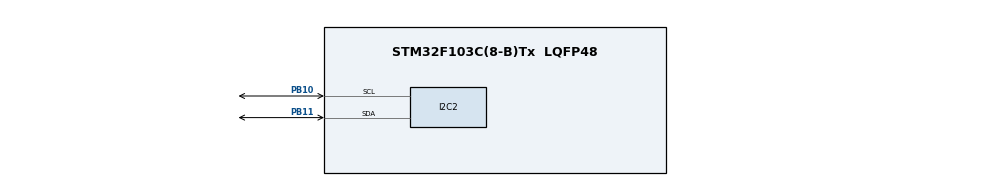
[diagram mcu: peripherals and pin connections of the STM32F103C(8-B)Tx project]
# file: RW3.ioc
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Mcu.Family=STM32F1
Mcu.Name=STM32F103C(8-B)Tx
Mcu.Package=LQFP48
NVIC.PriorityGroup=NVIC_PRIORITYGROUP_4
PA13.Mode=Serial_Wire
PA13.Signal=SYS_JTMS-SWDIO
PA14.Mode=Serial_Wire
PA14.Signal=SYS_JTCK-SWCLK
PB10.Mode=I2C
PB10.Signal=I2C2_SCL
PB11.Mode=I2C
PB11.Signal=I2C2_SDA
PD0-OSC_IN.Mode=HSE-External-Oscillator
PD0-OSC_IN.Signal=RCC_OSC_IN
PD1-OSC_OUT.Mode=HSE-External-Oscillator
PD1-OSC_OUT.Signal=RCC_OSC_OUT
ProjectManager.HeapSize=0x200
ProjectManager.StackSize=0x400
ProjectManager.TargetToolchain=MDK-ARM V5.32
RCC.AHBFreq_Value=72000000
RCC.APB1CLKDivider=RCC_HCLK_DIV2
RCC.APB1Freq_Value=36000000
RCC.APB1TimFreq_Value=72000000
RCC.APB2Freq_Value=72000000
RCC.APB2TimFreq_Value=72000000
RCC.HCLKFreq_Value=72000000
RCC.PLLMUL=RCC_PLL_MUL9
RCC.PLLSourceVirtual=RCC_PLLSOURCE_HSE
RCC.SYSCLKFreq_VALUE=72000000
RCC.SYSCLKSource=RCC_SYSCLKSOURCE_PLLCLK
RCC.USBFreq_Value=72000000
VP_TIM1_VS_ClockSourceINT.Mode=Internal
board=custom

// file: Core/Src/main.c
/* USER CODE BEGIN Header */
#include "main.h"
#include "i2c.h"
#include "tim.h"
#include "gpio.h"

/* USER CODE BEGIN Includes */
#include "u8g2.h"
/* USER CODE END Includes */

void SystemClock_Config(void);

/* USER CODE BEGIN 0 */
u8g2_t u8g2;
int x_offset = 0;

void Tims_delay_us(uint16_t us) {
    __HAL_TIM_SET_COUNTER(&htim1, 0);
    while (__HAL_TIM_GET_COUNTER(&htim1) < us);
}

uint8_t u8x8_byte_hw_i2c(u8x8_t *u8x8, uint8_t msg, uint8_t arg_int, void *arg_ptr) {
    static uint8_t buffer[128];
    static uint8_t buf_idx;
    uint8_t *data;

    switch (msg) {
    case U8X8_MSG_BYTE_INIT:
        break;
    case U8X8_MSG_BYTE_START_TRANSFER:
        buf_idx = 0;
        break;
    case U8X8_MSG_BYTE_SEND:
        data = (uint8_t *)arg_ptr;
        while (arg_int > 0) {
            buffer[buf_idx++] = *data;
            data++;
            arg_int--;
        }
        break;
    case U8X8_MSG_BYTE_END_TRANSFER:
        if (HAL_I2C_Master_Transmit(&hi2c2, 0x78, buffer, buf_idx, 1000) != HAL_OK)
            return 0;
        break;
    default:
        return 0;
    }
    return 1;
}

uint8_t u8x8_gpio_and_delay(u8x8_t *u8x8, uint8_t msg, uint8_t arg_int, void *arg_ptr) {
    switch (msg) {
    case U8X8_MSG_DELAY_100NANO:
        __NOP();
        break;
    case U8X8_MSG_DELAY_10MICRO:
        for (uint16_t n = 0; n < 320; n++) { __NOP(); }
        break;
    case U8X8_MSG_DELAY_MILLI:
        HAL_Delay(arg_int);
        break;
    case U8X8_MSG_DELAY_I2C:
        Tims_delay_us(5);
        break;
    default:
        u8x8_SetGPIOResult(u8x8, 1);
        break;
    }
    return 1;
}
/* USER CODE END 0 */

int main(void)
{
  HAL_Init();
  SystemClock_Config();
  MX_GPIO_Init();
  MX_I2C2_Init();
  MX_TIM1_Init();

  /* USER CODE BEGIN 2 */
  HAL_TIM_Base_Start(&htim1);

  u8g2_Setup_ssd1306_i2c_128x64_noname_f(&u8g2, U8G2_R0, u8x8_byte_hw_i2c, u8x8_gpio_and_delay);
  u8g2_InitDisplay(&u8g2);
  u8g2_SetPowerSave(&u8g2, 0);
  /* USER CODE END 2 */

  while (1)
  {
    /* USER CODE BEGIN 3 */
    u8g2_ClearBuffer(&u8g2);

    u8g2_DrawBox(&u8g2, 10, 10, 30, 30);
    u8g2_DrawCircle(&u8g2, 80, 30, 15, U8G2_DRAW_ALL);
    u8g2_DrawLine(&u8g2, 0, 0, 128, 64);
    u8g2_DrawLine(&u8g2, 0, 64, 128, 0);

    u8g2_DrawFrame(&u8g2, x_offset, 40, 16, 16);
    x_offset += 4;
    if (x_offset > 128) x_offset = 0;

    u8g2_SendBuffer(&u8g2);

    HAL_Delay(50);
    /* USER CODE END 3 */
  }
}

/* USER CODE BEGIN 4 */
void SystemClock_Config(void)
{
  RCC_OscInitTypeDef RCC_OscInitStruct = {0};
  RCC_ClkInitTypeDef RCC_ClkInitStruct = {0};

  RCC_OscInitStruct.OscillatorType = RCC_OSCILLATORTYPE_HSI;
  RCC_OscInitStruct.HSIState = RCC_HSI_ON;
  RCC_OscInitStruct.HSICalibrationValue = RCC_HSICALIBRATION_DEFAULT;
  RCC_OscInitStruct.PLL.PLLState = RCC_PLL_ON;
  RCC_OscInitStruct.PLL.PLLSource = RCC_PLLSOURCE_HSI_DIV2;
  RCC_OscInitStruct.PLL.PLLMUL = RCC_PLL_MUL9;
  if (HAL_RCC_OscConfig(&RCC_OscInitStruct) != HAL_OK) { Error_Handler(); }

  RCC_ClkInitStruct.ClockType = RCC_CLOCKTYPE_HCLK|RCC_CLOCKTYPE_SYSCLK
                              |RCC_CLOCKTYPE_PCLK1|RCC_CLOCKTYPE_PCLK2;
  RCC_ClkInitStruct.SYSCLKSource = RCC_SYSCLKSOURCE_PLLCLK;
  RCC_ClkInitStruct.AHBCLKDivider = RCC_SYSCLK_DIV1;
  RCC_ClkInitStruct.APB1CLKDivider = RCC_HCLK_DIV2;
  RCC_ClkInitStruct.APB2CLKDivider = RCC_HCLK_DIV1;

  if (HAL_RCC_ClockConfig(&RCC_ClkInitStruct, FLASH_LATENCY_1) != HAL_OK) { Error_Handler(); }
}
/* USER CODE END 4 */

void Error_Handler(void)
{
  __disable_irq();
  while (1)
  {
  }
}
